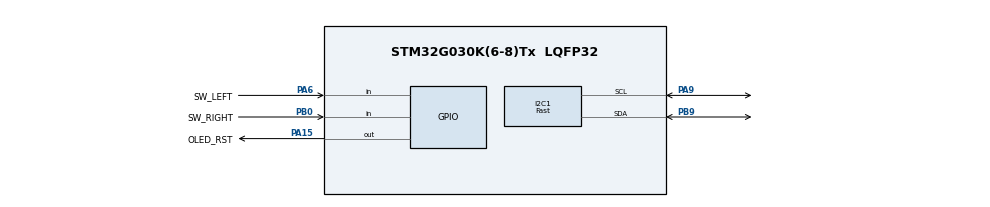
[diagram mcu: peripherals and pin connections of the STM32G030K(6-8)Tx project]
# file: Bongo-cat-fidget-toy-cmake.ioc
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I2C1.Analog_Filter=I2C_ANALOGFILTER_DISABLE
I2C1.I2C_Speed_Mode=I2C_Fast
I2C1.NoStretchMode=I2C_NOSTRETCH_ENABLE
I2C1.Timing=0x00601133
Mcu.Family=STM32G0
Mcu.Name=STM32G030K(6-8)Tx
Mcu.Package=LQFP32
NVIC.RCC_IRQn=true\:0\:0\:false\:true\:true\:1\:true\:false\:true
NVIC.TIM14_IRQn=true\:0\:0\:false\:true\:true\:2\:true\:true\:true
PA13.Mode=Serial_Wire
PA13.Signal=SYS_SWDIO
PA14-BOOT0.Mode=Serial_Wire
PA14-BOOT0.Signal=SYS_SWCLK
PA15.GPIO_Label=OLED_RST
PA15.Signal=GPIO_Output
PA6.GPIO_Label=SW_LEFT
PA6.Signal=GPIO_Input
PA9.GPIO_Pu=GPIO_PULLUP
PA9.GPIO_Speed=GPIO_SPEED_FREQ_VERY_HIGH
PA9.Mode=I2C
PA9.Signal=I2C1_SCL
PB0.GPIO_Label=SW_RIGHT
PB0.Signal=GPIO_Input
PB9.GPIO_Pu=GPIO_PULLUP
PB9.GPIO_Speed=GPIO_SPEED_FREQ_VERY_HIGH
PB9.Mode=I2C
PB9.Signal=I2C1_SDA
ProjectManager.HeapSize=0x200
ProjectManager.StackSize=0x400
ProjectManager.TargetToolchain=CMake
RCC.ADCFreq_Value=64000000
RCC.AHBCLKDivider=RCC_SYSCLK_DIV2
RCC.AHBFreq_Value=32000000
RCC.CortexFreq_Value=32000000
RCC.EXTERNAL_CLOCK_VALUE=12288000
RCC.HCLKFreq_Value=32000000
RCC.HSE_VALUE=8000000
RCC.HSI_VALUE=16000000
RCC.LSE_VALUE=32768
RCC.SYSCLKFreq_VALUE=64000000
RCC.SYSCLKSource=RCC_SYSCLKSOURCE_PLLCLK
RCC.VCOOutputFreq_Value=128000000
TIM14.Period=6400-1
TIM14.Prescaler=100-1
VP_TIM14_VS_ClockSourceINT.Mode=Enable_Timer
board=custom

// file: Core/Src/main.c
/* USER CODE BEGIN Header */
/**
  ******************************************************************************
  * @file           : main.c
  * @brief          : Main program body
  ******************************************************************************
  * @attention
  *
  * Copyright (c) 2026 STMicroelectronics.
  * All rights reserved.
  *
  * This software is licensed under terms that can be found in the LICENSE file
  * in the root directory of this software component.
  * If no LICENSE file comes with this software, it is provided AS-IS.
  *
  ******************************************************************************
  */
/* USER CODE END Header */
#include "main.h"

/* USER CODE BEGIN Includes */
#include "ssd1306.h"
#include "buttons.h"
#include "settings.h"
#include "tap_tracker.h"
#include "animation.h"
#include "ui.h"
/* USER CODE END Includes */

/* USER CODE BEGIN PTD */
typedef enum {
    IDLE,
    SWITCH,
} state_e;
/* USER CODE END PTD */

I2C_HandleTypeDef hi2c1;
TIM_HandleTypeDef htim14;

void SystemClock_Config(void);
static void MX_GPIO_Init(void);
static void MX_I2C1_Init(void);
static void MX_TIM14_Init(void);
static void MX_NVIC_Init(void);

/* USER CODE BEGIN 0 */
void HAL_TIM_PeriodElapsedCallback(TIM_HandleTypeDef *htim)
{
    if (htim == &htim14)
    {
        readPins();
    }
}
/* USER CODE END 0 */

int main(void)
{

  HAL_Init();

  SystemClock_Config();

  MX_GPIO_Init();
  MX_I2C1_Init();
  MX_TIM14_Init();
  MX_NVIC_Init();

  /* USER CODE BEGIN 2 */
  HAL_GPIO_WritePin(OLED_RST_GPIO_Port, OLED_RST_Pin, GPIO_PIN_RESET);
  HAL_Delay(10);
  HAL_GPIO_WritePin(OLED_RST_GPIO_Port, OLED_RST_Pin, GPIO_PIN_SET);
  ssd1306_Init();
  ssd1306_SetContrast(DISPLAY_CONTRAST);

  tap_tracker_reset();
  last_save_time = HAL_GetTick();

  handle_boot_overrides();
  load_settings();

  state_e state       = IDLE;
  uint8_t idle_cnt    = 0;
  int32_t idle_cntr   = 0;
  int32_t tap_left_cntr  = 0;
  int32_t tap_right_cntr = 0;
  uint8_t left_state  = 0;
  uint8_t right_state = 0;

  uint32_t idle_since      = 0;
  uint32_t sleep_zzz_timer = 0;
  uint8_t  sleep_zzz_frame = 0;

  HAL_TIM_Base_Start_IT(&htim14);

  while (1) {
    check_and_save();
    update_saved_indicator();
    update_tap_speed();

    switch (state) {
    case IDLE:
        if (sw_state_left == 0 || sw_state_right == 0) {
            if (!ssd1306_GetDisplayOn()) ssd1306_SetDisplayOn(1);
            state        = SWITCH;
            idle_since   = 0;
        } else {
            if (idle_since == 0) {
                idle_since      = HAL_GetTick();
                sleep_zzz_timer = idle_since;
                sleep_zzz_frame = 0;
            }

            uint32_t elapsed = HAL_GetTick() - idle_since;

            if (elapsed >= SLEEP_DELAY + DISPLAY_OFF_DELAY) {
                if (ssd1306_GetDisplayOn()) ssd1306_SetDisplayOn(0);
            } else if (elapsed >= SLEEP_DELAY) {
                draw_sleep_frame();
                draw_zzz_overlay(sleep_zzz_frame);
                update_display_with_overlays();
                if (HAL_GetTick() - sleep_zzz_timer >= SLEEP_ZZZ_PERIOD) {
                    sleep_zzz_frame = (sleep_zzz_frame + 1) % 4;
                    sleep_zzz_timer = HAL_GetTick();
                }
            } else {
                draw_idle_frame(idle_cnt);
                update_display_with_overlays();
                idle_cnt = (idle_cnt + 1) % idle_frame_count();
            }

            uint32_t t = HAL_GetTick();
            while (HAL_GetTick() - t < 100) __WFI();
        }
        break;

    case SWITCH:
        handle_display_mode_switch();

        if (check_idle_transition(&idle_cntr, &left_state, &right_state)) {
            state      = IDLE;
            idle_since = 0;
        } else if (!NONE_PRESSED) {
            handle_paw_animations(&left_state, &right_state,
                                  &tap_left_cntr, &tap_right_cntr, &idle_cntr);
        }

        if (pending_milestone) {
            HAL_TIM_Base_Stop_IT(&htim14);
            play_milestone_celebration(pending_milestone);
            pending_milestone = 0;
            HAL_TIM_Base_Start_IT(&htim14);
            readPins();
            while (!NONE_PRESSED) { readPins(); HAL_Delay(10); }
            left_state     = 0;
            right_state    = 0;
            tap_left_cntr  = 0;
            tap_right_cntr = 0;
            idle_cntr      = 0;
            tap_tracker_reset();
            save_settings();
        }

        handle_tap_decay(&tap_left_cntr, &tap_right_cntr);
        update_display_with_overlays();
        break;
    }
  }
  /* USER CODE END 2 */

  /* Infinite loop */
  while (1)
  {

  }
}

void SystemClock_Config(void)
{
  RCC_OscInitTypeDef RCC_OscInitStruct = {0};
  RCC_ClkInitTypeDef RCC_ClkInitStruct = {0};

  // SCALE2 supports up to 16MHz — no PLL needed, saves ~2mA vs SCALE1+PLL
  HAL_PWREx_ControlVoltageScaling(PWR_REGULATOR_VOLTAGE_SCALE2);

  RCC_OscInitStruct.OscillatorType = RCC_OSCILLATORTYPE_HSI;
  RCC_OscInitStruct.HSIState = RCC_HSI_ON;
  RCC_OscInitStruct.HSIDiv = RCC_HSI_DIV1;
  RCC_OscInitStruct.HSICalibrationValue = RCC_HSICALIBRATION_DEFAULT;
  RCC_OscInitStruct.PLL.PLLState = RCC_PLL_NONE;
  if (HAL_RCC_OscConfig(&RCC_OscInitStruct) != HAL_OK)
  {
    Error_Handler();
  }

  RCC_ClkInitStruct.ClockType = RCC_CLOCKTYPE_HCLK|RCC_CLOCKTYPE_SYSCLK
                              |RCC_CLOCKTYPE_PCLK1;
  RCC_ClkInitStruct.SYSCLKSource = RCC_SYSCLKSOURCE_HSI;  // 16MHz, no PLL
  RCC_ClkInitStruct.AHBCLKDivider = RCC_SYSCLK_DIV1;      // HCLK = 16MHz
  RCC_ClkInitStruct.APB1CLKDivider = RCC_HCLK_DIV1;       // PCLK1 = 16MHz

  if (HAL_RCC_ClockConfig(&RCC_ClkInitStruct, FLASH_LATENCY_1) != HAL_OK)
  {
    Error_Handler();
  }
}

/**
  * @brief NVIC Configuration.
  * @retval None
  */
static void MX_NVIC_Init(void)
{
  HAL_NVIC_SetPriority(RCC_IRQn, 0, 0);
  HAL_NVIC_EnableIRQ(RCC_IRQn);
  HAL_NVIC_SetPriority(TIM14_IRQn, 0, 0);
  HAL_NVIC_EnableIRQ(TIM14_IRQn);
}

static void MX_I2C1_Init(void)
{

  hi2c1.Instance = I2C1;
  hi2c1.Init.Timing = 0x00300619;  // 16MHz / FM 400kHz
  hi2c1.Init.OwnAddress1 = 0;
  hi2c1.Init.AddressingMode = I2C_ADDRESSINGMODE_7BIT;
  hi2c1.Init.DualAddressMode = I2C_DUALADDRESS_DISABLE;
  hi2c1.Init.OwnAddress2 = 0;
  hi2c1.Init.OwnAddress2Masks = I2C_OA2_NOMASK;
  hi2c1.Init.GeneralCallMode = I2C_GENERALCALL_DISABLE;
  hi2c1.Init.NoStretchMode = I2C_NOSTRETCH_ENABLE;
  if (HAL_I2C_Init(&hi2c1) != HAL_OK)
  {
    Error_Handler();
  }
  if (HAL_I2CEx_ConfigAnalogFilter(&hi2c1, I2C_ANALOGFILTER_DISABLE) != HAL_OK)
  {
    Error_Handler();
  }
  if (HAL_I2CEx_ConfigDigitalFilter(&hi2c1, 0) != HAL_OK)
  {
    Error_Handler();
  }
}

static void MX_TIM14_Init(void)
{

  htim14.Instance = TIM14;
  htim14.Init.Prescaler = 16-1;
  htim14.Init.CounterMode = TIM_COUNTERMODE_UP;
  htim14.Init.Period = 1000-1;  // 16MHz / 16 / 1000 = 1kHz (1ms)
  htim14.Init.ClockDivision = TIM_CLOCKDIVISION_DIV1;
  htim14.Init.AutoReloadPreload = TIM_AUTORELOAD_PRELOAD_DISABLE;
  if (HAL_TIM_Base_Init(&htim14) != HAL_OK)
  {
    Error_Handler();
  }
}

static void MX_GPIO_Init(void)
{
  GPIO_InitTypeDef GPIO_InitStruct = {0};

  __HAL_RCC_GPIOB_CLK_ENABLE();
  __HAL_RCC_GPIOC_CLK_ENABLE();
  __HAL_RCC_GPIOA_CLK_ENABLE();

  HAL_GPIO_WritePin(OLED_RST_GPIO_Port, OLED_RST_Pin, GPIO_PIN_RESET);

  GPIO_InitStruct.Pin = GPIO_PIN_14|GPIO_PIN_15|GPIO_PIN_6;
  GPIO_InitStruct.Mode = GPIO_MODE_ANALOG;
  GPIO_InitStruct.Pull = GPIO_NOPULL;
  HAL_GPIO_Init(GPIOC, &GPIO_InitStruct);

  GPIO_InitStruct.Pin = GPIO_PIN_0|GPIO_PIN_1|GPIO_PIN_2|GPIO_PIN_3
                        |GPIO_PIN_4|GPIO_PIN_5|GPIO_PIN_7|GPIO_PIN_8
                        |GPIO_PIN_10|GPIO_PIN_11|GPIO_PIN_12;
  GPIO_InitStruct.Mode = GPIO_MODE_ANALOG;
  GPIO_InitStruct.Pull = GPIO_NOPULL;
  HAL_GPIO_Init(GPIOA, &GPIO_InitStruct);

  GPIO_InitStruct.Pin = SW_LEFT_Pin;
  GPIO_InitStruct.Mode = GPIO_MODE_INPUT;
  GPIO_InitStruct.Pull = GPIO_NOPULL;
  HAL_GPIO_Init(SW_LEFT_GPIO_Port, &GPIO_InitStruct);

  GPIO_InitStruct.Pin = SW_RIGHT_Pin;
  GPIO_InitStruct.Mode = GPIO_MODE_INPUT;
  GPIO_InitStruct.Pull = GPIO_NOPULL;
  HAL_GPIO_Init(SW_RIGHT_GPIO_Port, &GPIO_InitStruct);

  GPIO_InitStruct.Pin = GPIO_PIN_1|GPIO_PIN_2|GPIO_PIN_3|GPIO_PIN_4
                        |GPIO_PIN_5|GPIO_PIN_6|GPIO_PIN_7|GPIO_PIN_8;
  GPIO_InitStruct.Mode = GPIO_MODE_ANALOG;
  GPIO_InitStruct.Pull = GPIO_NOPULL;
  HAL_GPIO_Init(GPIOB, &GPIO_InitStruct);

  GPIO_InitStruct.Pin = OLED_RST_Pin;
  GPIO_InitStruct.Mode = GPIO_MODE_OUTPUT_PP;
  GPIO_InitStruct.Pull = GPIO_NOPULL;
  GPIO_InitStruct.Speed = GPIO_SPEED_FREQ_LOW;
  HAL_GPIO_Init(OLED_RST_GPIO_Port, &GPIO_InitStruct);

}

void Error_Handler(void)
{
  __disable_irq();
  while (1)
  {
  }
}
